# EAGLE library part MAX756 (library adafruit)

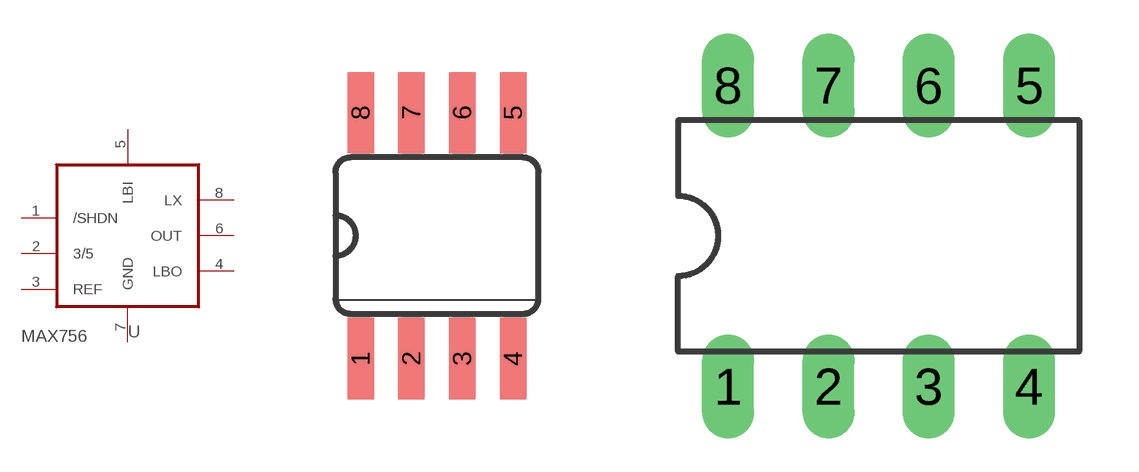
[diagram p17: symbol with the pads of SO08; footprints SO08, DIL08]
Designator prefix -

## MAX756CSA  [SO08]
1  /SHDN  in
2  3/5
3  REF  pas
4  LBO  in
5  LBI  in
6  OUT  out
7  GND  pwr
8  LX  out

## MAX756CPA  [DIL08]
Pads as for SO08

## Footprint SO08 (pad centres in mm)
smd 0.66 x 2.032: 1 -1.905,-3.073; 2 -0.635,-3.073; 3 0.635,-3.073; 4 1.905,-3.073; 5 1.905,3.073; 6 0.635,3.073; 7 -0.635,3.073; 8 -1.905,3.073

## Footprint DIL08 (pad centres in mm)
Dual In Line Package
drill 0.813 long: 1 -3.81,-3.81; 2 -1.27,-3.81; 3 1.27,-3.81; 4 3.81,-3.81; 5 3.81,3.81; 6 1.27,3.81; 7 -1.27,3.81; 8 -3.81,3.81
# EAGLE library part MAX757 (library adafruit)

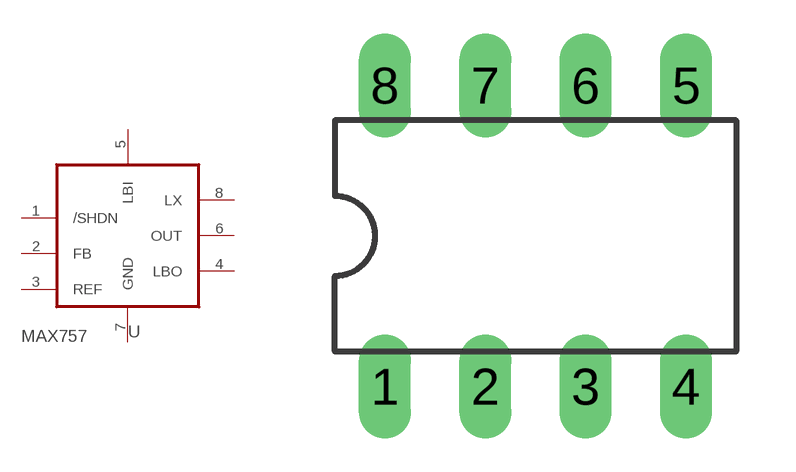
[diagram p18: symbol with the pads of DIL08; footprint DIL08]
Designator prefix -

## MAX757  [DIL08]
1  /SHDN  in
2  FB
3  REF  pas
4  LBO  in
5  LBI  in
6  OUT  out
7  GND  pwr
8  LX  out

## Footprint DIL08 (pad centres in mm)
Dual In Line Package
drill 0.813 long: 1 -3.81,-3.81; 2 -1.27,-3.81; 3 1.27,-3.81; 4 3.81,-3.81; 5 3.81,3.81; 6 1.27,3.81; 7 -1.27,3.81; 8 -3.81,3.81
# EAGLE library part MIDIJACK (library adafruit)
DIN 5 jack also known as MIDI jack A modification of conn-hirshman:MAB5SH with two options for the grounding 'teeth'

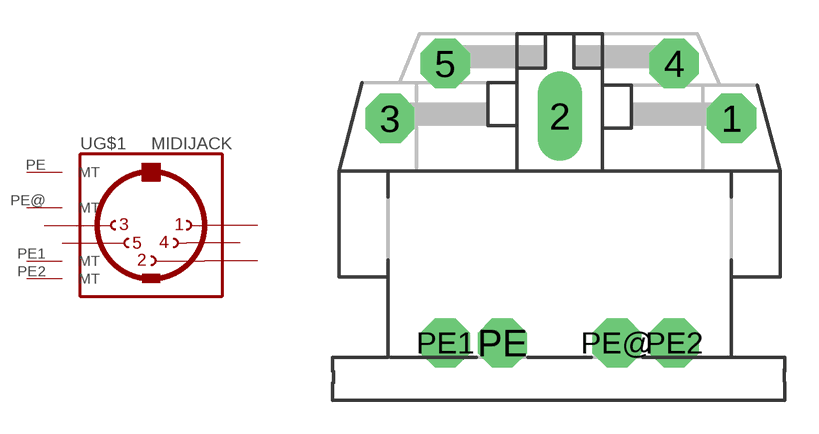
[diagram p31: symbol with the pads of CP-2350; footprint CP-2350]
Designator prefix -; gates G$2=MT G$3=MT G$1=DIN-5 G$4=MT G$5=MT

## MIDIJACK  [CP-2350]
1  G$1:1  pas
2  G$1:2  pas
3  G$1:3  pas
4  G$1:4  pas
5  G$1:5  pas
PE  G$2:MT  pas
PE1  G$4:MT  pas
PE2  G$5:MT  pas
PE@  G$3:MT  pas

## Footprint CP-2350 (pad centres in mm)
Female CONNECTOR 5 pins 90 deg. with shield, horizontal (DIN 41524)
drill 1.321 pad 2.184 octagon: 1 7.62,12.58; 3 -7.52,12.58; 4 5.08,15.02; 5 -5.08,15.02; PE -2.54,2.62; PE1 -5.08,2.62; PE2 5.08,2.62; PE@ 2.54,2.62
drill 1.321 long: 2 0,12.68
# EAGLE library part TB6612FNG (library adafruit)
TB6612FNG MOS dual H-bridge motor driver, 1.2A current 3.2A peak 3 or 5v logic and 3-15v motor

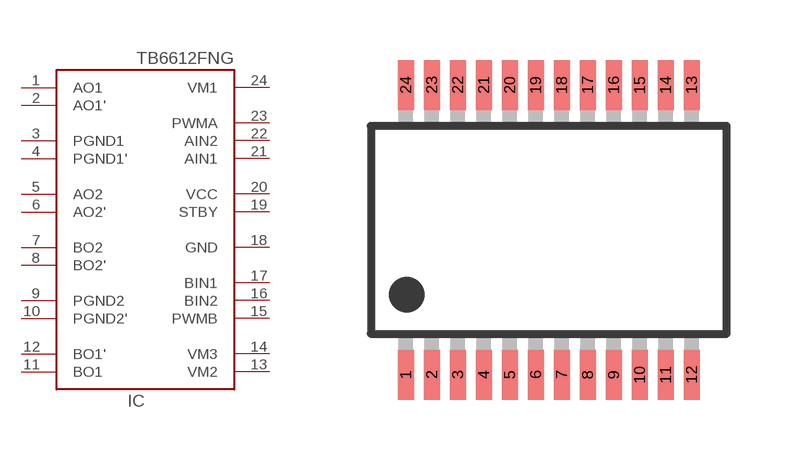
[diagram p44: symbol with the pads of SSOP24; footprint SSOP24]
Designator prefix IC

## TB6612FNG  [SSOP24]
1  AO1  out
2  AO1'  out
3  PGND1  pwr
4  PGND1'  pwr
5  AO2  out
6  AO2'  out
7  BO2  out
8  BO2'  out
9  PGND2  pwr
10  PGND2'  pwr
11  BO1  out
12  BO1'  out
13  VM2  pwr
14  VM3  pwr
15  PWMB  in
16  BIN2  in
17  BIN1  in
18  GND  pwr
19  STBY  in
20  VCC  pwr
21  AIN1  in
22  AIN2  in
23  PWMA  in
24  VM1  pwr

## Footprint SSOP24 (pad centres in mm)
Shrink Small Outline Package SSOP-24
smd 0.4 x 1.25: 1 -3.575,-3.625; 2 -2.925,-3.625; 3 -2.275,-3.625; 4 -1.625,-3.625; 5 -0.975,-3.625; 6 -0.325,-3.625; 7 0.325,-3.625; 8 0.975,-3.625; 9 1.625,-3.625; 10 2.275,-3.625; 11 2.925,-3.625; 12 3.575,-3.625; 13 3.575,3.625; 14 2.925,3.625; 15 2.275,3.625; 16 1.625,3.625; 17 0.975,3.625; 18 0.325,3.625; 19 -0.325,3.625; 20 -0.975,3.625; 21 -1.625,3.625; 22 -2.275,3.625; 23 -2.925,3.625; 24 -3.575,3.625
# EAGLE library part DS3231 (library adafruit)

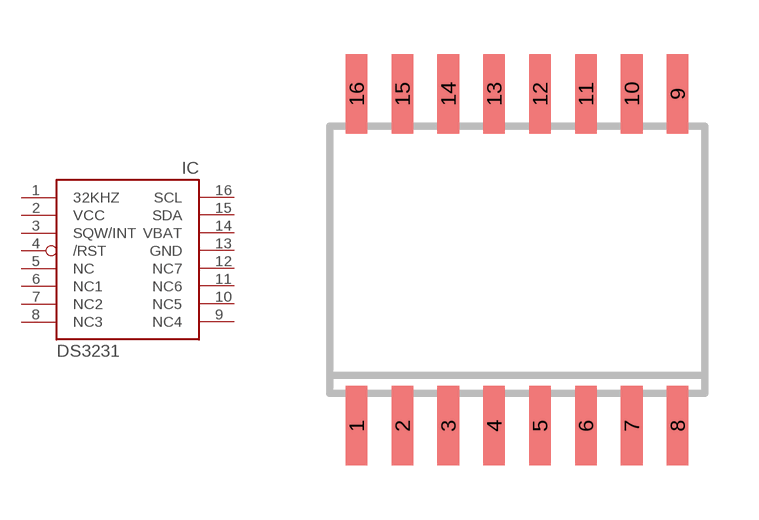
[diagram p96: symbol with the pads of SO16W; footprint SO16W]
Designator prefix IC

## DS3231/SO  [SO16W]
1  32KHZ  out
2  VCC  pwr
3  SQW/INT  out
4  /RST  pas
5  NC  nc
6  NC1  nc
7  NC2  nc
8  NC3  nc
9  NC4  nc
10  NC5  nc
11  NC6  nc
12  NC7  nc
13  GND  pwr
14  VBAT  pwr
15  SDA
16  SCL

## Footprint SO16W (pad centres in mm)
SMALL OUTLINE INTEGRATED CIRCUIT wide body 7.5 mm/JEDEC MS-013AA
smd 0.6 x 2.2: 1 -4.445,-4.6; 2 -3.175,-4.6; 3 -1.905,-4.6; 4 -0.635,-4.6; 5 0.635,-4.6; 6 1.905,-4.6; 7 3.175,-4.6; 8 4.445,-4.6; 9 4.445,4.6; 10 3.175,4.6; 11 1.905,4.6; 12 0.635,4.6; 13 -0.635,4.6; 14 -1.905,4.6; 15 -3.175,4.6; 16 -4.445,4.6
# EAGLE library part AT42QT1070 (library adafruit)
QTouch 5-channel standalone sensor IC AT42QT1070 in standalone mode has 5 inputs (guard + 4 key) and open drain outputs. 1.8V-5.5V power.

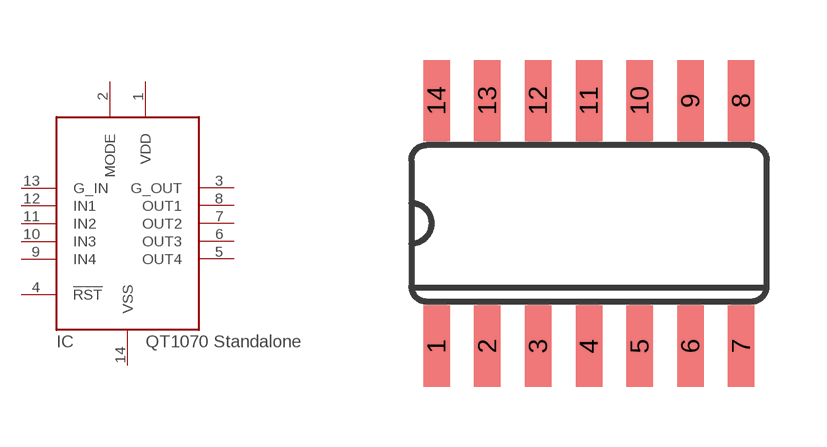
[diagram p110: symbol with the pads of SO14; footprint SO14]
Designator prefix IC

## AT42QT1070-SSU  [SO14]
1  VDD  pwr
2  MODE  in
3  G_OUT  oc
4  !RST  in
5  OUT4  oc
6  OUT3  oc
7  OUT2  oc
8  OUT1  oc
9  IN4  in
10  IN3  in
11  IN2  in
12  IN1  in
13  G_IN  in
14  VSS  pwr

## Footprint SO14 (pad centres in mm)
Small Outline package 150 mil
smd 0.66 x 2.032: 1 -3.81,-3.073; 2 -2.54,-3.073; 3 -1.27,-3.073; 4 0,-3.073; 5 1.27,-3.073; 6 2.54,-3.073; 7 3.81,-3.073; 8 3.81,3.073; 9 2.54,3.073; 10 1.27,3.073; 11 0,3.073; 12 -1.27,3.073; 13 -2.54,3.073; 14 -3.81,3.073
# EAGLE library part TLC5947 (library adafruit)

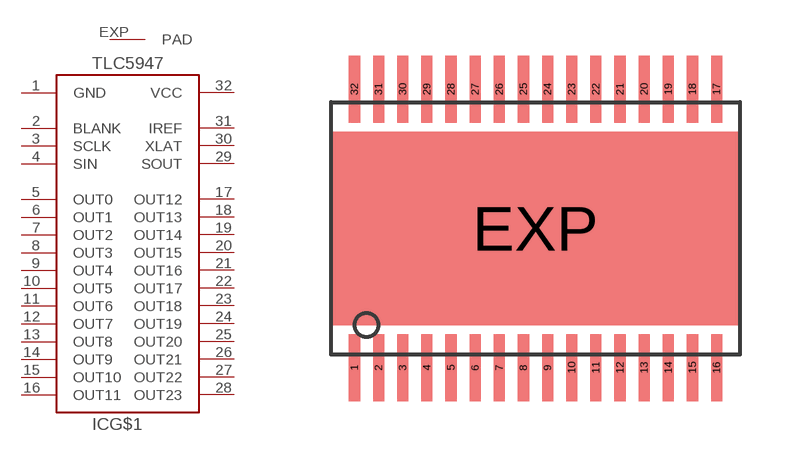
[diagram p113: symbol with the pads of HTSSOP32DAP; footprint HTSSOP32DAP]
Designator prefix IC; gates G$1=TLC5947 G$2=THERMAL_PAD

## TLC5947-DAP  [HTSSOP32DAP]
1  G$1:GND  pwr
2  G$1:BLANK  in
3  G$1:SCLK  in
4  G$1:SIN  in
5  G$1:OUT0  oc
6  G$1:OUT1  oc
7  G$1:OUT2  oc
8  G$1:OUT3  oc
9  G$1:OUT4  oc
10  G$1:OUT5  oc
11  G$1:OUT6  oc
12  G$1:OUT7  oc
13  G$1:OUT8  oc
14  G$1:OUT9  oc
15  G$1:OUT10  oc
16  G$1:OUT11  oc
17  G$1:OUT12  oc
18  G$1:OUT13  oc
19  G$1:OUT14  oc
20  G$1:OUT15  oc
21  G$1:OUT16  oc
22  G$1:OUT17  oc
23  G$1:OUT18  oc
24  G$1:OUT19  oc
25  G$1:OUT20  oc
26  G$1:OUT21  oc
27  G$1:OUT22  oc
28  G$1:OUT23  oc
29  G$1:SOUT  out
30  G$1:XLAT  in
31  G$1:IREF
32  G$1:VCC  pwr
EXP  G$2:PAD  pas

## Footprint HTSSOP32DAP (pad centres in mm)
PowerPAD(TM) PLASTIC SMALL-OUTLINE PACKAGE DAP (R-PDSO-G**) Source: http://focus.ti.com/lit/ml/mpds029b/mpds029b.pdf / slma002.pdf
smd 0.3 x 1.8: 1 -4.875,-3.75; 2 -4.225,-3.75; 3 -3.575,-3.75; 4 -2.925,-3.75; 5 -2.275,-3.75; 6 -1.625,-3.75; 7 -0.975,-3.75; 8 -0.325,-3.75; 9 0.325,-3.75; 10 0.975,-3.75; 11 1.625,-3.75; 12 2.275,-3.75; 13 2.925,-3.75; 14 3.575,-3.75; 15 4.225,-3.75; 16 4.875,-3.75; 17 4.875,3.75; 18 4.225,3.75; 19 3.575,3.75; 20 2.925,3.75; 21 2.275,3.75; 22 1.625,3.75; 23 0.975,3.75; 24 0.325,3.75; 25 -0.325,3.75; 26 -0.975,3.75; 27 -1.625,3.75; 28 -2.275,3.75; 29 -2.925,3.75; 30 -3.575,3.75; 31 -4.225,3.75; 32 -4.875,3.75
smd 11 x 5.2: EXP 0,0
